VERSION 5.8 ;
BUSBITCHARS "[]" ;
DIVIDERCHAR "/" ;

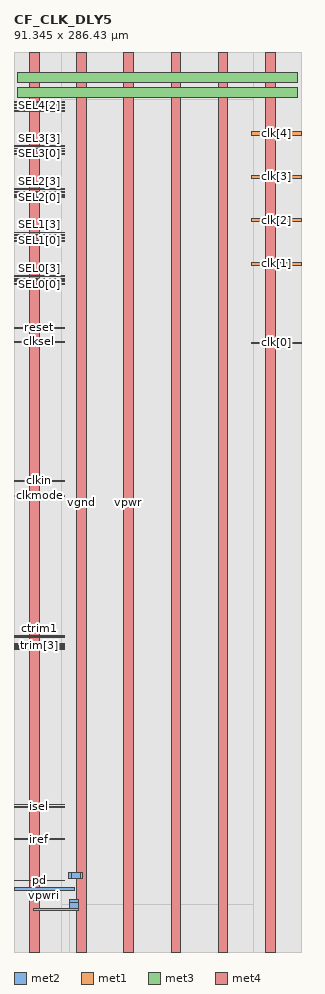
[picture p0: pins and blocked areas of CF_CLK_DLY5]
MACRO CF_CLK_DLY5
  CLASS BLOCK ;
  ORIGIN 0 0 ;
  FOREIGN CF_CLK_DLY5 0 0 ;
  SIZE 91.345 BY 286.43 ;
  PIN vpwri
    DIRECTION OUTPUT ;
    USE SIGNAL ;
    PORT
      LAYER met2 ;
        RECT 0 19.6 19.3 20.6 ;
    END
  END vpwri
  PIN sleep
    DIRECTION INPUT ;
    USE SIGNAL ;
    PORT
      LAYER met1 ;
        RECT 0 46.795 16.14 47.085 ;
    END
  END sleep
  PIN SEL0[0]
    DIRECTION INPUT ;
    USE SIGNAL ;
    PORT
      LAYER met1 ;
        RECT 0 212.41 16.14 212.67 ;
    END
  END SEL0[0]
  PIN SEL4[0]
    DIRECTION INPUT ;
    USE SIGNAL ;
    PORT
      LAYER met1 ;
        RECT 0 267.65 16.14 267.91 ;
    END
  END SEL4[0]
  PIN SEL4[2]
    DIRECTION INPUT ;
    USE SIGNAL ;
    PORT
      LAYER met1 ;
        RECT 0 269.41 16.14 269.67 ;
    END
  END SEL4[2]
  PIN SEL4[1]
    DIRECTION INPUT ;
    USE SIGNAL ;
    PORT
      LAYER met1 ;
        RECT 0 268.53 16.14 268.79 ;
    END
  END SEL4[1]
  PIN SEL3[3]
    DIRECTION INPUT ;
    USE SIGNAL ;
    PORT
      LAYER met1 ;
        RECT 0 256.48 16.14 256.74 ;
    END
  END SEL3[3]
  PIN SEL3[2]
    DIRECTION INPUT ;
    USE SIGNAL ;
    PORT
      LAYER met1 ;
        RECT 0 255.6 16.14 255.86 ;
    END
  END SEL3[2]
  PIN SEL3[1]
    DIRECTION INPUT ;
    USE SIGNAL ;
    PORT
      LAYER met1 ;
        RECT 0 254.72 16.14 254.98 ;
    END
  END SEL3[1]
  PIN SEL3[0]
    DIRECTION INPUT ;
    USE SIGNAL ;
    PORT
      LAYER met1 ;
        RECT 0 253.84 16.14 254.1 ;
    END
  END SEL3[0]
  PIN SEL2[3]
    DIRECTION INPUT ;
    USE SIGNAL ;
    PORT
      LAYER met1 ;
        RECT 0 242.67 16.14 242.93 ;
    END
  END SEL2[3]
  PIN SEL2[2]
    DIRECTION INPUT ;
    USE SIGNAL ;
    PORT
      LAYER met1 ;
        RECT 0 241.79 16.14 242.05 ;
    END
  END SEL2[2]
  PIN SEL2[1]
    DIRECTION INPUT ;
    USE SIGNAL ;
    PORT
      LAYER met1 ;
        RECT 0 240.91 16.14 241.17 ;
    END
  END SEL2[1]
  PIN SEL2[0]
    DIRECTION INPUT ;
    USE SIGNAL ;
    PORT
      LAYER met1 ;
        RECT 0 240.03 16.14 240.29 ;
    END
  END SEL2[0]
  PIN SEL0[1]
    DIRECTION INPUT ;
    USE SIGNAL ;
    PORT
      LAYER met1 ;
        RECT 0 213.29 16.14 213.55 ;
    END
  END SEL0[1]
  PIN SEL1[3]
    DIRECTION INPUT ;
    USE SIGNAL ;
    PORT
      LAYER met1 ;
        RECT 0 228.86 16.14 229.12 ;
    END
  END SEL1[3]
  PIN SEL1[2]
    DIRECTION INPUT ;
    USE SIGNAL ;
    PORT
      LAYER met1 ;
        RECT 0 227.98 16.14 228.24 ;
    END
  END SEL1[2]
  PIN SEL1[1]
    DIRECTION INPUT ;
    USE SIGNAL ;
    PORT
      LAYER met1 ;
        RECT 0 227.1 16.14 227.36 ;
    END
  END SEL1[1]
  PIN SEL1[0]
    DIRECTION INPUT ;
    USE SIGNAL ;
    PORT
      LAYER met1 ;
        RECT 0 226.22 16.14 226.48 ;
    END
  END SEL1[0]
  PIN SEL0[3]
    DIRECTION INPUT ;
    USE SIGNAL ;
    PORT
      LAYER met1 ;
        RECT 0 215.05 16.14 215.31 ;
    END
  END SEL0[3]
  PIN SEL0[2]
    DIRECTION INPUT ;
    USE SIGNAL ;
    PORT
      LAYER met1 ;
        RECT 0 214.17 16.14 214.43 ;
    END
  END SEL0[2]
  PIN clkmode
    DIRECTION INPUT ;
    USE SIGNAL ;
    PORT
      LAYER met1 ;
        RECT 0 145.05 16.14 145.34 ;
    END
  END clkmode
  PIN clkin
    DIRECTION INPUT ;
    USE SIGNAL ;
    PORT
      LAYER met1 ;
        RECT 0 149.86 16.14 150.15 ;
    END
  END clkin
  PIN SEL4[3]
    DIRECTION INPUT ;
    USE SIGNAL ;
    PORT
      LAYER met1 ;
        RECT 0 270.29 16.14 270.55 ;
    END
  END SEL4[3]
  PIN ctrim0
    DIRECTION INPUT ;
    USE SIGNAL ;
    PORT
      LAYER met1 ;
        RECT 0 99.955 16.14 100.245 ;
    END
  END ctrim0
  PIN clksel
    DIRECTION INPUT ;
    USE SIGNAL ;
    PORT
      LAYER met1 ;
        RECT 0 194.03 16.14 194.32 ;
    END
  END clksel
  PIN trim[2]
    DIRECTION INPUT ;
    USE SIGNAL ;
    PORT
      LAYER met1 ;
        RECT 0 96.985 16.14 97.275 ;
    END
  END trim[2]
  PIN trim[1]
    DIRECTION INPUT ;
    USE SIGNAL ;
    PORT
      LAYER met1 ;
        RECT 0 96.555 16.14 96.845 ;
    END
  END trim[1]
  PIN trim[0]
    DIRECTION INPUT ;
    USE SIGNAL ;
    PORT
      LAYER met1 ;
        RECT 0 96.125 16.14 96.415 ;
    END
  END trim[0]
  PIN reset
    DIRECTION INPUT ;
    USE SIGNAL ;
    PORT
      LAYER met1 ;
        RECT 0 198.5 16.14 198.79 ;
    END
  END reset
  PIN pd
    DIRECTION INPUT ;
    USE SIGNAL ;
    PORT
      LAYER met1 ;
        RECT 0 22.6 16.14 22.89 ;
    END
  END pd
  PIN isel
    DIRECTION INPUT ;
    USE SIGNAL ;
    PORT
      LAYER met1 ;
        RECT 0 46.005 16.14 46.295 ;
    END
  END isel
  PIN iref
    DIRECTION INPUT ;
    USE SIGNAL ;
    PORT
      LAYER met1 ;
        RECT 0 35.725 16.14 36.015 ;
    END
  END iref
  PIN ctrim1
    DIRECTION INPUT ;
    USE SIGNAL ;
    PORT
      LAYER met1 ;
        RECT 0 100.495 16.14 100.785 ;
    END
  END ctrim1
  PIN trim[3]
    DIRECTION INPUT ;
    USE SIGNAL ;
    PORT
      LAYER met1 ;
        RECT 0 97.415 16.14 97.7 ;
    END
  END trim[3]
  PIN trim[4]
    DIRECTION INPUT ;
    USE SIGNAL ;
    PORT
      LAYER met1 ;
        RECT 0 97.845 16.14 98.135 ;
    END
  END trim[4]
  PIN vgnd
    DIRECTION INPUT ;
    USE GROUND ;
    PORT
      LAYER met2 ;
        RECT 17.42 23.39 18.42 25.395 ;
        RECT 17.42 23.39 21.79 25.395 ;
      LAYER met3 ;
        RECT 21.31 23.39 21.79 25.395 ;
        RECT 1.23 271.93 90.115 275.03 ;
      LAYER met4 ;
        RECT 20 0 23.1 286.43 ;
        RECT 50 0 53.1 286.43 ;
        RECT 80 0 83.1 286.43 ;
    END
  END vgnd
  PIN vpwr
    DIRECTION INPUT ;
    USE POWER ;
    PORT
      LAYER met2 ;
        RECT 17.51 15.61 20.575 16.61 ;
        RECT 17.51 13.24 20.575 16.61 ;
      LAYER met3 ;
        RECT 6.31 13.24 20.575 13.72 ;
        RECT 1.23 276.73 90.115 279.83 ;
      LAYER met4 ;
        RECT 5 0 8.1 286.43 ;
        RECT 35 0 38.1 286.43 ;
        RECT 65 0 68.1 286.43 ;
    END
  END vpwr
  PIN clk[0]
    DIRECTION OUTPUT ;
    USE SIGNAL ;
    PORT
      LAYER met1 ;
        RECT 75.46 193.755 91.345 193.985 ;
    END
  END clk[0]
  PIN clk[1]
    DIRECTION OUTPUT ;
    USE SIGNAL ;
    PORT
      LAYER met1 ;
        RECT 75.46 218.53 91.345 219.575 ;
    END
  END clk[1]
  PIN clk[2]
    DIRECTION OUTPUT ;
    USE SIGNAL ;
    PORT
      LAYER met1 ;
        RECT 75.46 232.34 91.345 233.385 ;
    END
  END clk[2]
  PIN clk[3]
    DIRECTION OUTPUT ;
    USE SIGNAL ;
    PORT
      LAYER met1 ;
        RECT 75.46 246.15 91.345 247.195 ;
    END
  END clk[3]
  PIN clk[4]
    DIRECTION OUTPUT ;
    USE SIGNAL ;
    PORT
      LAYER met1 ;
        RECT 75.46 259.96 91.345 261.005 ;
    END
  END clk[4]
  OBS
    LAYER li1 ;
      RECT 0 0 91.345 286.43 ;
    LAYER met1 ;
      RECT 0 0 15 22.6 ;
      RECT 0 22.89 15 35.725 ;
      RECT 0 36.015 15 46.005 ;
      RECT 0 46.295 15 46.795 ;
      RECT 0 47.085 15 96.125 ;
      RECT 0 96.415 15 96.555 ;
      RECT 0 96.845 15 96.985 ;
      RECT 0 97.275 15 97.415 ;
      RECT 0 97.7 15 97.845 ;
      RECT 0 98.135 15 99.955 ;
      RECT 0 100.245 15 100.495 ;
      RECT 0 100.785 15 145.05 ;
      RECT 0 145.34 15 149.86 ;
      RECT 0 150.15 15 194.03 ;
      RECT 0 194.32 15 198.5 ;
      RECT 0 198.79 15 212.41 ;
      RECT 0 212.67 15 213.29 ;
      RECT 0 213.55 15 214.17 ;
      RECT 0 214.43 15 215.05 ;
      RECT 0 215.31 15 226.22 ;
      RECT 0 226.48 15 227.1 ;
      RECT 0 227.36 15 227.98 ;
      RECT 0 228.24 15 228.86 ;
      RECT 0 229.12 15 240.03 ;
      RECT 0 240.29 15 240.91 ;
      RECT 0 241.17 15 241.79 ;
      RECT 0 242.05 15 242.67 ;
      RECT 0 242.93 15 253.84 ;
      RECT 0 254.1 15 254.72 ;
      RECT 0 254.98 15 255.6 ;
      RECT 0 255.86 15 256.48 ;
      RECT 0 256.74 15 267.65 ;
      RECT 0 267.91 15 268.53 ;
      RECT 0 268.79 15 269.41 ;
      RECT 0 269.67 15 270.29 ;
      RECT 0 270.55 15 286.43 ;
      RECT 76.345 0 91.345 193.755 ;
      RECT 76.345 193.985 91.345 218.53 ;
      RECT 76.345 219.575 91.345 232.34 ;
      RECT 76.345 233.385 91.345 246.15 ;
      RECT 76.345 247.195 91.345 259.96 ;
      RECT 76.345 261.005 91.345 286.43 ;
      RECT 15 0 76.345 15 ;
      RECT 15 271.43 76.345 286.43 ;
    LAYER met2 ;
      RECT 0 0 15 19.6 ;
      RECT 0 20.6 15 286.43 ;
      RECT 76.345 0 91.345 286.43 ;
      RECT 15 0 17.51 15 ;
      RECT 17.51 0 20.575 13.24 ;
      RECT 20.575 0 76.345 15 ;
      RECT 15 271.43 76.345 286.43 ;
  END
END CF_CLK_DLY5

END LIBRARY
